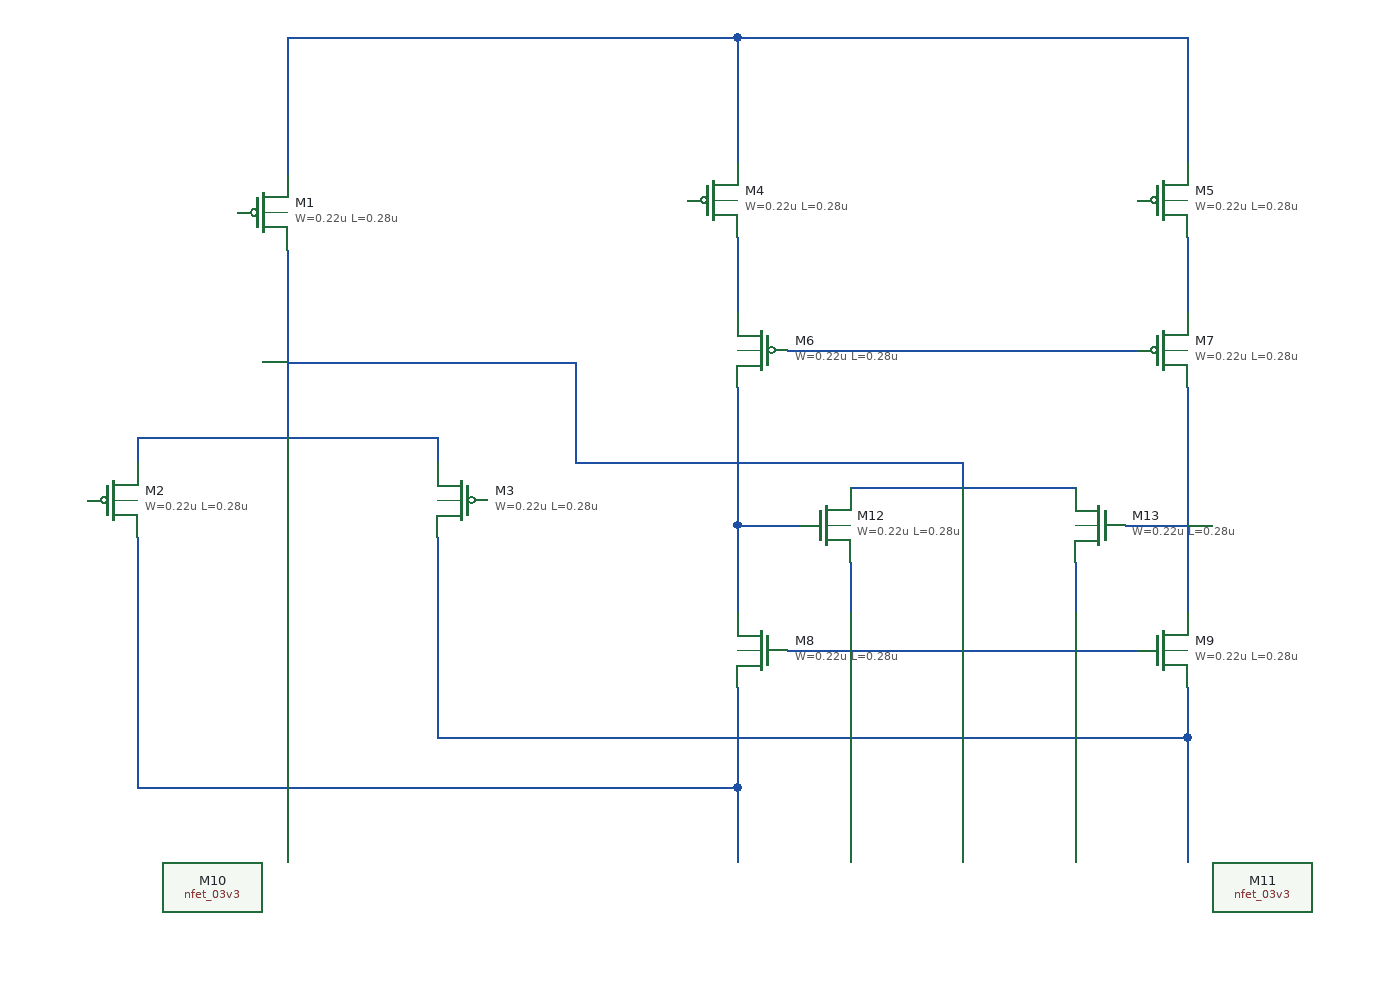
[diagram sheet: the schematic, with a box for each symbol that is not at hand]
v {xschem version=3.4.8RC file_version=1.3}
G {}
K {}
V {}
S {}
F {}
E {}
N 100 -460 100 -440 {lab=#net1}
N 100 -460 340 -460 {lab=#net1}
N 340 -460 340 -440 {lab=#net1}
N 220 -490 220 -460 {lab=#net1}
N 220 -610 220 -490 {lab=#net1}
N 100 -380 100 -340 {lab=#net2}
N 100 -340 100 -180 {lab=#net2}
N 100 -180 580 -180 {lab=#net2}
N 580 -180 580 -120 {lab=#net2}
N 580 -260 580 -180 {lab=#net2}
N 580 -780 580 -680 {lab=#net3}
N 580 -780 820 -780 {lab=#net3}
N 940 -780 940 -680 {lab=#net3}
N 220 -780 580 -780 {lab=#net3}
N 220 -780 220 -670 {lab=#net3}
N 340 -380 340 -220 {lab=#net4}
N 340 -220 820 -220 {lab=#net4}
N 940 -220 940 -120 {lab=#net4}
N 940 -260 940 -220 {lab=#net4}
N 940 -440 940 -320 {lab=#net5}
N 620 -290 780 -290 {lab=#net6}
N 620 -530 770 -530 {lab=#net7}
N 890 -530 900 -530 {lab=#net7}
N 820 -220 940 -220 {lab=#net4}
N 780 -290 900 -290 {lab=#net6}
N 770 -530 890 -530 {lab=#net7}
N 820 -780 940 -780 {lab=#net3}
N 920 -390 940 -390 {lab=#net5}
N 670 -420 850 -420 {lab=#net1}
N 670 -360 670 -340 {lab=#net8}
N 670 -340 670 -320 {lab=#net8}
N 850 -360 850 -320 {lab=#net9}
N 760 -440 760 -420 {lab=#net1}
N 580 -620 580 -560 {lab=#net10}
N 940 -620 940 -560 {lab=#net11}
N 580 -390 630 -390 {lab=#net12}
N 940 -500 940 -440 {lab=#net5}
N 890 -390 920 -390 {lab=#net5}
N 450 -440 760 -440 {lab=#net1}
N 450 -520 450 -440 {lab=#net1}
N 220 -520 450 -520 {lab=#net1}
N 580 -500 580 -390 {lab=#net12}
N 580 -390 580 -320 {lab=#net12}
C {symbols/pfet_03v3.sym} 80 -410 0 0 {name=M2
L=0.28u
W=0.22u
nf=1
m=1
ad="'int((nf+1)/2) * W/nf * 0.18u'"
pd="'2*int((nf+1)/2) * (W/nf + 0.18u)'"
as="'int((nf+2)/2) * W/nf * 0.18u'"
ps="'2*int((nf+2)/2) * (W/nf + 0.18u)'"
nrd="'0.18u / W'" nrs="'0.18u / W'"
sa=0 sb=0 sd=0
model=pfet_03v3
spiceprefix=X
}
C {symbols/pfet_03v3.sym} 360 -410 0 1 {name=M3
L=0.28u
W=0.22u
nf=1
m=1
ad="'int((nf+1)/2) * W/nf * 0.18u'"
pd="'2*int((nf+1)/2) * (W/nf + 0.18u)'"
as="'int((nf+2)/2) * W/nf * 0.18u'"
ps="'2*int((nf+2)/2) * (W/nf + 0.18u)'"
nrd="'0.18u / W'" nrs="'0.18u / W'"
sa=0 sb=0 sd=0
model=pfet_03v3
spiceprefix=X
}
C {symbols/pfet_03v3.sym} 200 -640 0 0 {name=M1
L=0.28u
W=0.22u
nf=1
m=1
ad="'int((nf+1)/2) * W/nf * 0.18u'"
pd="'2*int((nf+1)/2) * (W/nf + 0.18u)'"
as="'int((nf+2)/2) * W/nf * 0.18u'"
ps="'2*int((nf+2)/2) * (W/nf + 0.18u)'"
nrd="'0.18u / W'" nrs="'0.18u / W'"
sa=0 sb=0 sd=0
model=pfet_03v3
spiceprefix=X
}
C {symbols/pfet_03v3.sym} 560 -650 0 0 {name=M4
L=0.28u
W=0.22u
nf=1
m=1
ad="'int((nf+1)/2) * W/nf * 0.18u'"
pd="'2*int((nf+1)/2) * (W/nf + 0.18u)'"
as="'int((nf+2)/2) * W/nf * 0.18u'"
ps="'2*int((nf+2)/2) * (W/nf + 0.18u)'"
nrd="'0.18u / W'" nrs="'0.18u / W'"
sa=0 sb=0 sd=0
model=pfet_03v3
spiceprefix=X
}
C {symbols/pfet_03v3.sym} 920 -650 0 0 {name=M5
L=0.28u
W=0.22u
nf=1
m=1
ad="'int((nf+1)/2) * W/nf * 0.18u'"
pd="'2*int((nf+1)/2) * (W/nf + 0.18u)'"
as="'int((nf+2)/2) * W/nf * 0.18u'"
ps="'2*int((nf+2)/2) * (W/nf + 0.18u)'"
nrd="'0.18u / W'" nrs="'0.18u / W'"
sa=0 sb=0 sd=0
model=pfet_03v3
spiceprefix=X
}
C {symbols/pfet_03v3.sym} 600 -530 0 1 {name=M6
L=0.28u
W=0.22u
nf=1
m=1
ad="'int((nf+1)/2) * W/nf * 0.18u'"
pd="'2*int((nf+1)/2) * (W/nf + 0.18u)'"
as="'int((nf+2)/2) * W/nf * 0.18u'"
ps="'2*int((nf+2)/2) * (W/nf + 0.18u)'"
nrd="'0.18u / W'" nrs="'0.18u / W'"
sa=0 sb=0 sd=0
model=pfet_03v3
spiceprefix=X
}
C {symbols/pfet_03v3.sym} 920 -530 0 0 {name=M7
L=0.28u
W=0.22u
nf=1
m=1
ad="'int((nf+1)/2) * W/nf * 0.18u'"
pd="'2*int((nf+1)/2) * (W/nf + 0.18u)'"
as="'int((nf+2)/2) * W/nf * 0.18u'"
ps="'2*int((nf+2)/2) * (W/nf + 0.18u)'"
nrd="'0.18u / W'" nrs="'0.18u / W'"
sa=0 sb=0 sd=0
model=pfet_03v3
spiceprefix=X
}
C {symbols/nfet_03v3.sym} 600 -290 0 1 {name=M8
L=0.28u
W=0.22u
nf=1
m=1
ad="'int((nf+1)/2) * W/nf * 0.18u'"
pd="'2*int((nf+1)/2) * (W/nf + 0.18u)'"
as="'int((nf+2)/2) * W/nf * 0.18u'"
ps="'2*int((nf+2)/2) * (W/nf + 0.18u)'"
nrd="'0.18u / W'" nrs="'0.18u / W'"
sa=0 sb=0 sd=0
model=nfet_03v3
spiceprefix=X
}
C {symbols/nfet_03v3.sym} 920 -290 0 0 {name=M9
L=0.28u
W=0.22u
nf=1
m=1
ad="'int((nf+1)/2) * W/nf * 0.18u'"
pd="'2*int((nf+1)/2) * (W/nf + 0.18u)'"
as="'int((nf+2)/2) * W/nf * 0.18u'"
ps="'2*int((nf+2)/2) * (W/nf + 0.18u)'"
nrd="'0.18u / W'" nrs="'0.18u / W'"
sa=0 sb=0 sd=0
model=nfet_03v3
spiceprefix=X
}
C {symbols/nfet_03v3.sym} 560 -90 0 0 {name=M10
L=0.28u
W=0.22u
nf=1
m=1
ad="'int((nf+1)/2) * W/nf * 0.18u'"
pd="'2*int((nf+1)/2) * (W/nf + 0.18u)'"
as="'int((nf+2)/2) * W/nf * 0.18u'"
ps="'2*int((nf+2)/2) * (W/nf + 0.18u)'"
nrd="'0.18u / W'" nrs="'0.18u / W'"
sa=0 sb=0 sd=0
model=nfet_03v3
spiceprefix=X
}
C {symbols/nfet_03v3.sym} 920 -90 0 0 {name=M11
L=0.28u
W=0.22u
nf=1
m=1
ad="'int((nf+1)/2) * W/nf * 0.18u'"
pd="'2*int((nf+1)/2) * (W/nf + 0.18u)'"
as="'int((nf+2)/2) * W/nf * 0.18u'"
ps="'2*int((nf+2)/2) * (W/nf + 0.18u)'"
nrd="'0.18u / W'" nrs="'0.18u / W'"
sa=0 sb=0 sd=0
model=nfet_03v3
spiceprefix=X
}
C {symbols/nfet_03v3.sym} 650 -390 0 0 {name=M12
L=0.28u
W=0.22u
nf=1
m=1
ad="'int((nf+1)/2) * W/nf * 0.18u'"
pd="'2*int((nf+1)/2) * (W/nf + 0.18u)'"
as="'int((nf+2)/2) * W/nf * 0.18u'"
ps="'2*int((nf+2)/2) * (W/nf + 0.18u)'"
nrd="'0.18u / W'" nrs="'0.18u / W'"
sa=0 sb=0 sd=0
model=nfet_03v3
spiceprefix=X
}
C {symbols/nfet_03v3.sym} 870 -390 0 1 {name=M13
L=0.28u
W=0.22u
nf=1
m=1
ad="'int((nf+1)/2) * W/nf * 0.18u'"
pd="'2*int((nf+1)/2) * (W/nf + 0.18u)'"
as="'int((nf+2)/2) * W/nf * 0.18u'"
ps="'2*int((nf+2)/2) * (W/nf + 0.18u)'"
nrd="'0.18u / W'" nrs="'0.18u / W'"
sa=0 sb=0 sd=0
model=nfet_03v3
spiceprefix=X
}
